VERSION 5.8 ;
BUSBITCHARS "[]" ;
DIVIDERCHAR "/" ;

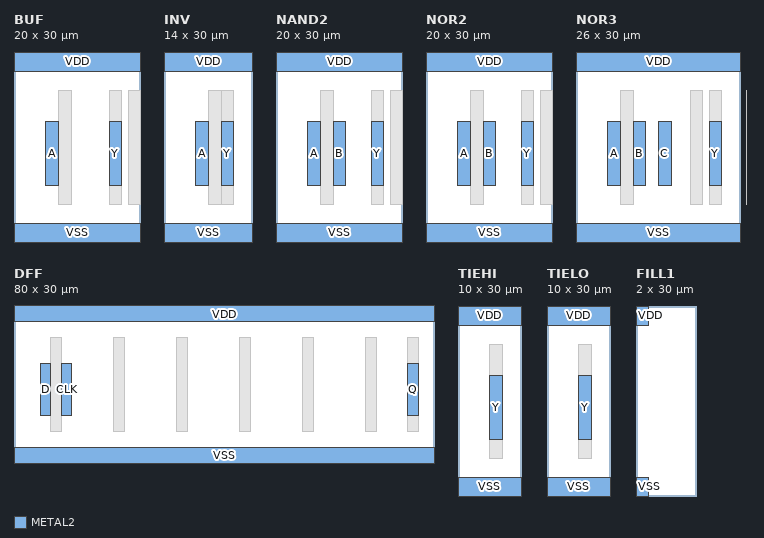
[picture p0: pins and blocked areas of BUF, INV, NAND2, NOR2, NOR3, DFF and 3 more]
MACRO BUF
  CLASS CORE ;
  ORIGIN 0 0 ;
  FOREIGN BUF 0 0 ;
  SIZE 20 BY 30 ;
  SYMMETRY X Y ;
  SITE core ;
  PIN A
    DIRECTION INPUT ;
    USE SIGNAL ;
    PORT
      LAYER METAL2 ;
        RECT 5 9 7 19 ;
    END
  END A
  PIN Y
    DIRECTION OUTPUT ;
    USE SIGNAL ;
    PORT
      LAYER METAL2 ;
        RECT 15 9 17 19 ;
    END
  END Y
  PIN VDD
    DIRECTION INOUT ;
    USE POWER ;
    SHAPE ABUTMENT ;
    PORT
      LAYER METAL2 ;
        RECT 0 27 20 30 ;
    END
  END VDD
  PIN VSS
    DIRECTION INOUT ;
    USE GROUND ;
    SHAPE ABUTMENT ;
    PORT
      LAYER METAL2 ;
        RECT 0 0 20 3 ;
    END
  END VSS
  OBS
    LAYER GATE ;
      RECT 7 6 9 24 ;
      RECT 18 6 20 24 ;
      RECT 15 6 17 24 ;
  END
END BUF

MACRO INV
  CLASS CORE ;
  ORIGIN 0 0 ;
  FOREIGN INV 0 0 ;
  SIZE 14 BY 30 ;
  SYMMETRY X Y ;
  SITE core ;
  PIN A
    DIRECTION INPUT ;
    USE SIGNAL ;
    PORT
      LAYER METAL2 ;
        RECT 5 9 7 19 ;
    END
  END A
  PIN Y
    DIRECTION OUTPUT ;
    USE SIGNAL ;
    PORT
      LAYER METAL2 ;
        RECT 9 9 11 19 ;
    END
  END Y
  PIN VDD
    DIRECTION INOUT ;
    USE POWER ;
    SHAPE ABUTMENT ;
    PORT
      LAYER METAL2 ;
        RECT 0 27 14 30 ;
    END
  END VDD
  PIN VSS
    DIRECTION INOUT ;
    USE GROUND ;
    SHAPE ABUTMENT ;
    PORT
      LAYER METAL2 ;
        RECT 0 0 14 3 ;
    END
  END VSS
  OBS
    LAYER GATE ;
      RECT 7 6 9 24 ;
      RECT 9 6 11 24 ;
  END
END INV

MACRO NAND2
  CLASS CORE ;
  ORIGIN 0 0 ;
  FOREIGN NAND2 0 0 ;
  SIZE 20 BY 30 ;
  SYMMETRY X Y ;
  SITE core ;
  PIN A
    DIRECTION INPUT ;
    USE SIGNAL ;
    PORT
      LAYER METAL2 ;
        RECT 5 9 7 19 ;
    END
  END A
  PIN B
    DIRECTION INPUT ;
    USE SIGNAL ;
    PORT
      LAYER METAL2 ;
        RECT 9 9 11 19 ;
    END
  END B
  PIN Y
    DIRECTION OUTPUT ;
    USE SIGNAL ;
    PORT
      LAYER METAL2 ;
        RECT 15 9 17 19 ;
    END
  END Y
  PIN VDD
    DIRECTION INOUT ;
    USE POWER ;
    SHAPE ABUTMENT ;
    PORT
      LAYER METAL2 ;
        RECT 0 27 20 30 ;
    END
  END VDD
  PIN VSS
    DIRECTION INOUT ;
    USE GROUND ;
    SHAPE ABUTMENT ;
    PORT
      LAYER METAL2 ;
        RECT 0 0 20 3 ;
    END
  END VSS
  OBS
    LAYER GATE ;
      RECT 7 6 9 24 ;
      RECT 18 6 20 24 ;
      RECT 15 6 17 24 ;
  END
END NAND2

MACRO NOR2
  CLASS CORE ;
  ORIGIN 0 0 ;
  FOREIGN NOR2 0 0 ;
  SIZE 20 BY 30 ;
  SYMMETRY X Y ;
  SITE core ;
  PIN A
    DIRECTION INPUT ;
    USE SIGNAL ;
    PORT
      LAYER METAL2 ;
        RECT 5 9 7 19 ;
    END
  END A
  PIN B
    DIRECTION INPUT ;
    USE SIGNAL ;
    PORT
      LAYER METAL2 ;
        RECT 9 9 11 19 ;
    END
  END B
  PIN Y
    DIRECTION OUTPUT ;
    USE SIGNAL ;
    PORT
      LAYER METAL2 ;
        RECT 15 9 17 19 ;
    END
  END Y
  PIN VDD
    DIRECTION INOUT ;
    USE POWER ;
    SHAPE ABUTMENT ;
    PORT
      LAYER METAL2 ;
        RECT 0 27 20 30 ;
    END
  END VDD
  PIN VSS
    DIRECTION INOUT ;
    USE GROUND ;
    SHAPE ABUTMENT ;
    PORT
      LAYER METAL2 ;
        RECT 0 0 20 3 ;
    END
  END VSS
  OBS
    LAYER GATE ;
      RECT 7 6 9 24 ;
      RECT 18 6 20 24 ;
      RECT 15 6 17 24 ;
  END
END NOR2

MACRO NOR3
  CLASS CORE ;
  ORIGIN 0 0 ;
  FOREIGN NOR3 0 0 ;
  SIZE 26 BY 30 ;
  SYMMETRY X Y ;
  SITE core ;
  PIN A
    DIRECTION INPUT ;
    USE SIGNAL ;
    PORT
      LAYER METAL2 ;
        RECT 5 9 7 19 ;
    END
  END A
  PIN B
    DIRECTION INPUT ;
    USE SIGNAL ;
    PORT
      LAYER METAL2 ;
        RECT 9 9 11 19 ;
    END
  END B
  PIN C
    DIRECTION INPUT ;
    USE SIGNAL ;
    PORT
      LAYER METAL2 ;
        RECT 13 9 15 19 ;
    END
  END C
  PIN Y
    DIRECTION OUTPUT ;
    USE SIGNAL ;
    PORT
      LAYER METAL2 ;
        RECT 21 9 23 19 ;
    END
  END Y
  PIN VDD
    DIRECTION INOUT ;
    USE POWER ;
    SHAPE ABUTMENT ;
    PORT
      LAYER METAL2 ;
        RECT 0 27 26 30 ;
    END
  END VDD
  PIN VSS
    DIRECTION INOUT ;
    USE GROUND ;
    SHAPE ABUTMENT ;
    PORT
      LAYER METAL2 ;
        RECT 0 0 26 3 ;
    END
  END VSS
  OBS
    LAYER GATE ;
      RECT 7 6 9 24 ;
      RECT 18 6 20 24 ;
      RECT 29 6 31 24 ;
      RECT 21 6 23 24 ;
  END
END NOR3

MACRO DFF
  CLASS CORE ;
  ORIGIN 0 0 ;
  FOREIGN DFF 0 0 ;
  SIZE 80 BY 30 ;
  SYMMETRY X Y ;
  SITE core ;
  PIN D
    DIRECTION INPUT ;
    USE SIGNAL ;
    PORT
      LAYER METAL2 ;
        RECT 5 9 7 19 ;
    END
  END D
  PIN CLK
    DIRECTION INPUT ;
    USE CLOCK ;
    PORT
      LAYER METAL2 ;
        RECT 9 9 11 19 ;
    END
  END CLK
  PIN Q
    DIRECTION OUTPUT ;
    USE SIGNAL ;
    PORT
      LAYER METAL2 ;
        RECT 75 9 77 19 ;
    END
  END Q
  PIN VDD
    DIRECTION INOUT ;
    USE POWER ;
    SHAPE ABUTMENT ;
    PORT
      LAYER METAL2 ;
        RECT 0 27 80 30 ;
    END
  END VDD
  PIN VSS
    DIRECTION INOUT ;
    USE GROUND ;
    SHAPE ABUTMENT ;
    PORT
      LAYER METAL2 ;
        RECT 0 0 80 3 ;
    END
  END VSS
  OBS
    LAYER GATE ;
      RECT 7 6 9 24 ;
      RECT 19 6 21 24 ;
      RECT 31 6 33 24 ;
      RECT 43 6 45 24 ;
      RECT 55 6 57 24 ;
      RECT 67 6 69 24 ;
      RECT 75 6 77 24 ;
  END
END DFF

MACRO TIEHI
  CLASS CORE ;
  ORIGIN 0 0 ;
  FOREIGN TIEHI 0 0 ;
  SIZE 10 BY 30 ;
  SYMMETRY X Y ;
  SITE core ;
  PIN Y
    DIRECTION OUTPUT ;
    USE SIGNAL ;
    PORT
      LAYER METAL2 ;
        RECT 5 9 7 19 ;
    END
  END Y
  PIN VDD
    DIRECTION INOUT ;
    USE POWER ;
    SHAPE ABUTMENT ;
    PORT
      LAYER METAL2 ;
        RECT 0 27 10 30 ;
    END
  END VDD
  PIN VSS
    DIRECTION INOUT ;
    USE GROUND ;
    SHAPE ABUTMENT ;
    PORT
      LAYER METAL2 ;
        RECT 0 0 10 3 ;
    END
  END VSS
  OBS
    LAYER GATE ;
      RECT 5 6 7 24 ;
  END
END TIEHI

MACRO TIELO
  CLASS CORE ;
  ORIGIN 0 0 ;
  FOREIGN TIELO 0 0 ;
  SIZE 10 BY 30 ;
  SYMMETRY X Y ;
  SITE core ;
  PIN Y
    DIRECTION OUTPUT ;
    USE SIGNAL ;
    PORT
      LAYER METAL2 ;
        RECT 5 9 7 19 ;
    END
  END Y
  PIN VDD
    DIRECTION INOUT ;
    USE POWER ;
    SHAPE ABUTMENT ;
    PORT
      LAYER METAL2 ;
        RECT 0 27 10 30 ;
    END
  END VDD
  PIN VSS
    DIRECTION INOUT ;
    USE GROUND ;
    SHAPE ABUTMENT ;
    PORT
      LAYER METAL2 ;
        RECT 0 0 10 3 ;
    END
  END VSS
  OBS
    LAYER GATE ;
      RECT 5 6 7 24 ;
  END
END TIELO

MACRO FILL1
  CLASS CORE SPACER ;
  ORIGIN 0 0 ;
  FOREIGN FILL1 0 0 ;
  SIZE 2 BY 30 ;
  SYMMETRY X Y ;
  SITE core ;
  PIN VDD
    DIRECTION INOUT ;
    USE POWER ;
    SHAPE ABUTMENT ;
    PORT
      LAYER METAL2 ;
        RECT 0 27 2 30 ;
    END
  END VDD
  PIN VSS
    DIRECTION INOUT ;
    USE GROUND ;
    SHAPE ABUTMENT ;
    PORT
      LAYER METAL2 ;
        RECT 0 0 2 3 ;
    END
  END VSS
END FILL1

END LIBRARY
